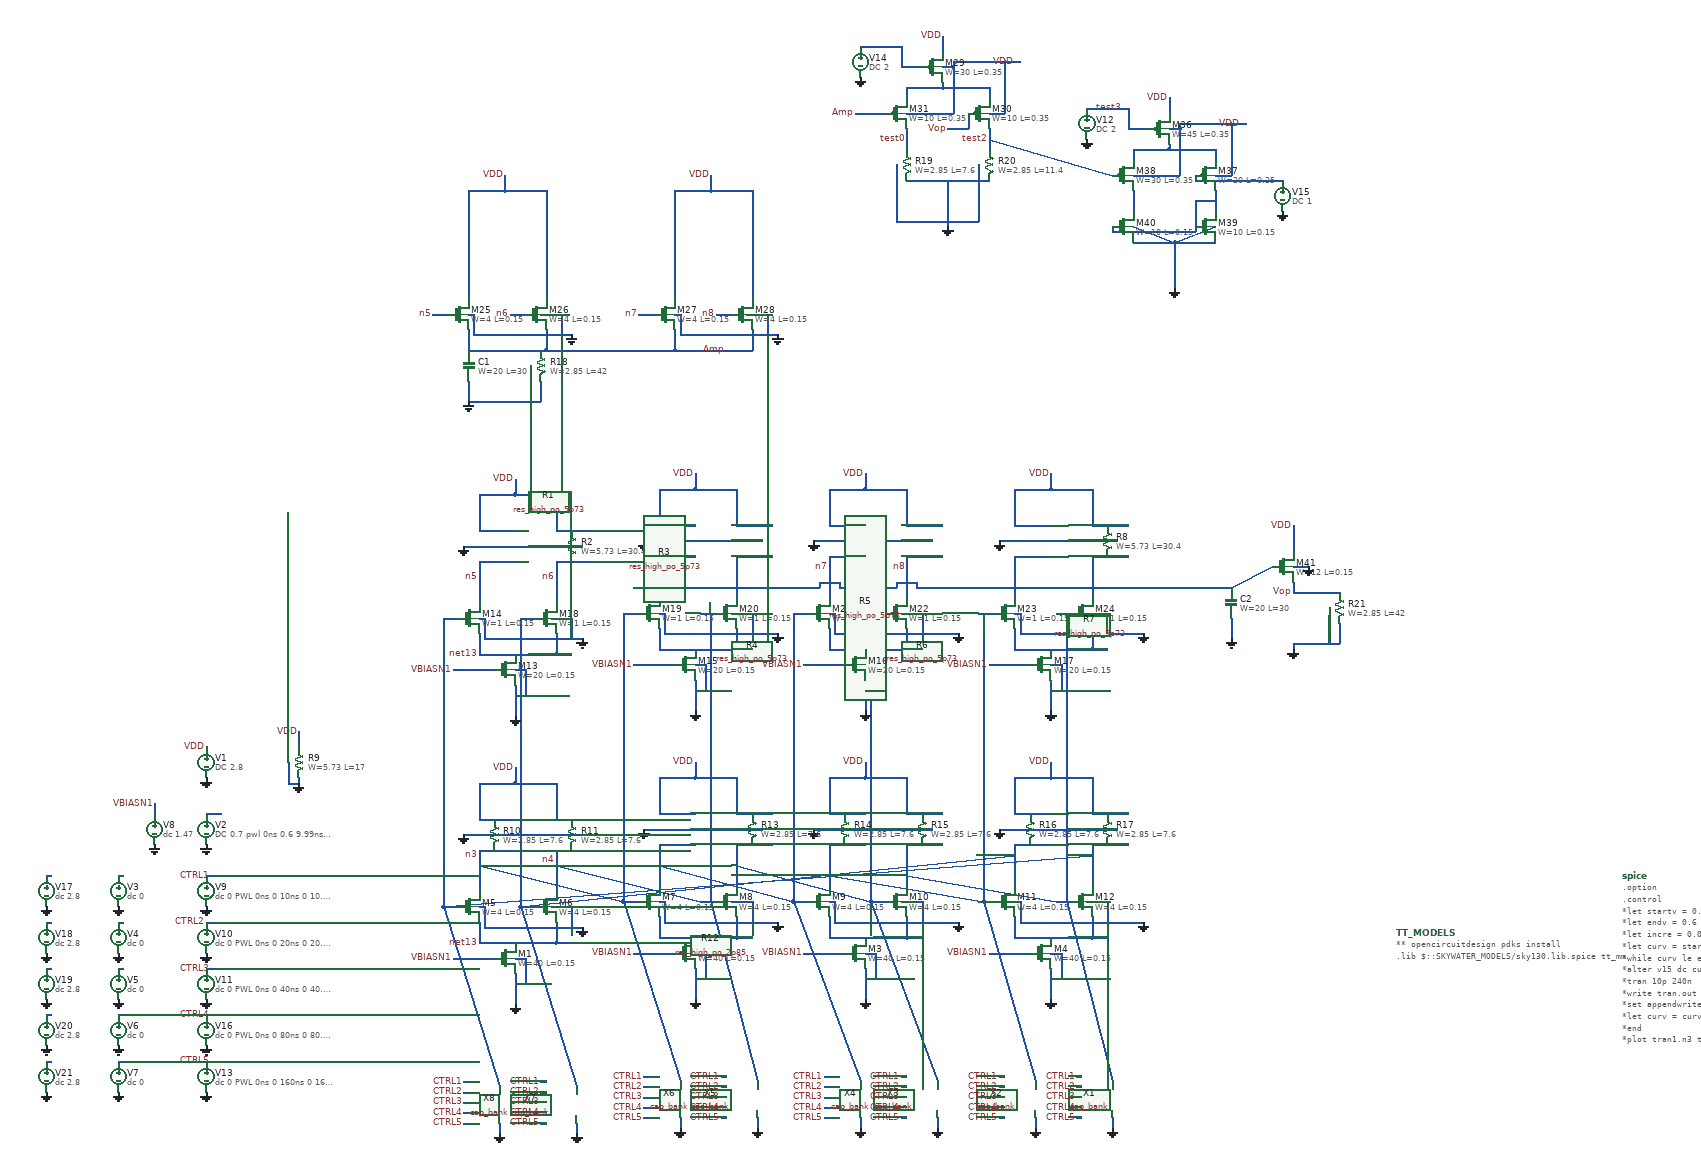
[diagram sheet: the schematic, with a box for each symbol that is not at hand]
v {xschem version=3.0.0 file_version=1.2 }
G {}
K {}
V {}
S {}
E {}
N 520 -180 520 -140 {
lab=GND}
N 450 -240 520 -240 {
lab=net13}
N 450 -280 450 -240 {
lab=net13}
N 520 -240 600 -240 {
lab=net13}
N 600 -280 600 -240 {
lab=net13}
N 600 -420 600 -340 {
lab=n4}
N 600 -550 600 -480 {
lab=VDD}
N 520 -550 600 -550 {
lab=VDD}
N 520 -580 520 -550 {
lab=VDD}
N 450 -550 520 -550 {
lab=VDD}
N 450 -550 450 -480 {
lab=VDD}
N 450 -420 450 -340 {
lab=n3}
N 380 -310 410 -310 {
lab=#net1}
N 530 -310 560 -310 {
lab=#net2}
N 400 -210 480 -210 {
lab=VBIASN1}
N 450 -310 460 -310 {
lab=GND}
N 520 -140 520 -120 {
lab=GND}
N 520 -210 540 -210 {
lab=GND}
N 540 -210 540 -160 {
lab=GND}
N 520 -160 540 -160 {
lab=GND}
N 590 -310 600 -310 {
lab=GND}
N 600 -310 630 -310 {
lab=GND}
N 600 -240 630 -240 {
lab=net13}
N 430 -450 580 -450 {
lab=GND}
N 420 -450 430 -450 {
lab=GND}
N 870 -190 870 -150 {
lab=GND}
N 800 -250 870 -250 {
lab=#net3}
N 800 -290 800 -250 {
lab=#net3}
N 870 -250 950 -250 {
lab=#net3}
N 950 -290 950 -250 {
lab=#net3}
N 950 -430 950 -350 {
lab=#net4}
N 950 -560 950 -490 {
lab=VDD}
N 870 -560 950 -560 {
lab=VDD}
N 870 -590 870 -560 {
lab=VDD}
N 800 -560 870 -560 {
lab=VDD}
N 800 -560 800 -490 {
lab=VDD}
N 800 -430 800 -350 {
lab=#net5}
N 730 -320 760 -320 {
lab=n3}
N 880 -320 910 -320 {
lab=n4}
N 750 -220 830 -220 {
lab=VBIASN1}
N 800 -320 810 -320 {
lab=GND}
N 870 -150 870 -130 {
lab=GND}
N 870 -220 890 -220 {
lab=GND}
N 890 -220 890 -170 {
lab=GND}
N 870 -170 890 -170 {
lab=GND}
N 940 -320 950 -320 {
lab=GND}
N 950 -320 980 -320 {
lab=GND}
N 950 -250 980 -250 {
lab=#net3}
N 780 -460 930 -460 {
lab=GND}
N 770 -460 780 -460 {
lab=GND}
N 1200 -190 1200 -150 {
lab=GND}
N 1130 -250 1200 -250 {
lab=#net6}
N 1130 -290 1130 -250 {
lab=#net6}
N 1200 -250 1280 -250 {
lab=#net6}
N 1280 -290 1280 -250 {
lab=#net6}
N 1280 -430 1280 -350 {
lab=#net7}
N 1280 -560 1280 -490 {
lab=VDD}
N 1200 -560 1280 -560 {
lab=VDD}
N 1200 -590 1200 -560 {
lab=VDD}
N 1130 -560 1200 -560 {
lab=VDD}
N 1130 -560 1130 -490 {
lab=VDD}
N 1130 -430 1130 -350 {
lab=#net8}
N 1060 -320 1090 -320 {
lab=#net5}
N 1210 -320 1240 -320 {
lab=#net4}
N 1080 -220 1160 -220 {
lab=VBIASN1}
N 1130 -320 1140 -320 {
lab=GND}
N 1200 -150 1200 -130 {
lab=GND}
N 1200 -220 1220 -220 {
lab=GND}
N 1220 -220 1220 -170 {
lab=GND}
N 1200 -170 1220 -170 {
lab=GND}
N 1270 -320 1280 -320 {
lab=GND}
N 1280 -320 1310 -320 {
lab=GND}
N 1280 -250 1310 -250 {
lab=#net6}
N 1110 -460 1260 -460 {
lab=GND}
N 1100 -460 1110 -460 {
lab=GND}
N 450 -390 730 -320 {
lab=n3}
N 600 -390 880 -320 {
lab=n4}
N 800 -390 1060 -320 {
lab=#net5}
N 950 -390 1210 -320 {
lab=#net4}
N 460 -310 460 -270 {
lab=GND}
N 460 -270 650 -270 {
lab=GND}
N 630 -310 630 -270 {
lab=GND}
N 810 -320 810 -280 {
lab=GND}
N 810 -280 1030 -280 {
lab=GND}
N 980 -320 980 -280 {
lab=GND}
N 1140 -320 1140 -280 {
lab=GND}
N 1140 -280 1380 -280 {
lab=GND}
N 1310 -320 1310 -280 {
lab=GND}
N 1560 -190 1560 -150 {
lab=GND}
N 1490 -250 1560 -250 {
lab=#net9}
N 1490 -290 1490 -250 {
lab=#net9}
N 1560 -250 1640 -250 {
lab=#net9}
N 1640 -290 1640 -250 {
lab=#net9}
N 1640 -430 1640 -350 {
lab=#net1}
N 1640 -560 1640 -490 {
lab=VDD}
N 1560 -560 1640 -560 {
lab=VDD}
N 1560 -590 1560 -560 {
lab=VDD}
N 1490 -560 1560 -560 {
lab=VDD}
N 1490 -560 1490 -490 {
lab=VDD}
N 1490 -430 1490 -350 {
lab=#net2}
N 1420 -320 1450 -320 {
lab=#net8}
N 1570 -320 1600 -320 {
lab=#net7}
N 1440 -220 1520 -220 {
lab=VBIASN1}
N 1490 -320 1500 -320 {
lab=GND}
N 1560 -150 1560 -130 {
lab=GND}
N 1560 -220 1580 -220 {
lab=GND}
N 1580 -220 1580 -170 {
lab=GND}
N 1560 -170 1580 -170 {
lab=GND}
N 1630 -320 1640 -320 {
lab=GND}
N 1640 -320 1670 -320 {
lab=GND}
N 1640 -250 1670 -250 {
lab=#net9}
N 1470 -460 1620 -460 {
lab=GND}
N 1460 -460 1470 -460 {
lab=GND}
N 1500 -320 1500 -280 {
lab=GND}
N 1500 -280 1740 -280 {
lab=GND}
N 1670 -320 1670 -280 {
lab=GND}
N 1130 -370 1430 -320 {
lab=#net8}
N 1280 -370 1570 -320 {
lab=#net7}
N 380 -310 1640 -410 {
lab=#net1}
N 530 -310 1490 -410 {
lab=#net2}
N -80 -490 -50 -490 {
lab=#net10}
N -80 -10 -70 -10 {
lab=CTRL5}
N -80 -100 -60 -100 {
lab=CTRL4}
N -80 -190 -60 -190 {
lab=CTRL3}
N -80 -280 -60 -280 {
lab=CTRL2}
N -80 -370 -60 -370 {
lab=CTRL1}
N -250 -370 -240 -370 {
lab=#net11}
N -250 -280 -240 -280 {
lab=#net12}
N -250 -190 -240 -190 {
lab=#net14}
N -250 -100 -240 -100 {
lab=#net15}
N -250 -10 -240 -10 {
lab=#net16}
N 450 -480 480 -480 {
lab=VDD}
N 480 -480 520 -480 {
lab=VDD}
N 480 -420 520 -420 {
lab=n3}
N 450 -420 480 -420 {
lab=n3}
N 600 -480 630 -480 {
lab=VDD}
N 630 -480 670 -480 {
lab=VDD}
N 630 -420 670 -420 {
lab=n4}
N 600 -420 630 -420 {
lab=n4}
N 800 -490 830 -490 {
lab=VDD}
N 830 -490 870 -490 {
lab=VDD}
N 830 -430 870 -430 {
lab=#net5}
N 800 -430 830 -430 {
lab=#net5}
N 950 -490 980 -490 {
lab=VDD}
N 980 -490 1020 -490 {
lab=VDD}
N 980 -430 1020 -430 {
lab=#net4}
N 950 -430 980 -430 {
lab=#net4}
N 1130 -490 1160 -490 {
lab=VDD}
N 1160 -490 1200 -490 {
lab=VDD}
N 1160 -430 1200 -430 {
lab=#net8}
N 1130 -430 1160 -430 {
lab=#net8}
N 1280 -490 1310 -490 {
lab=VDD}
N 1310 -490 1350 -490 {
lab=VDD}
N 1310 -430 1350 -430 {
lab=#net7}
N 1280 -430 1310 -430 {
lab=#net7}
N 1490 -490 1520 -490 {
lab=VDD}
N 1520 -490 1560 -490 {
lab=VDD}
N 1520 -430 1560 -430 {
lab=#net2}
N 1490 -430 1520 -430 {
lab=#net2}
N 1640 -490 1670 -490 {
lab=VDD}
N 1670 -490 1710 -490 {
lab=VDD}
N 1670 -430 1710 -430 {
lab=#net1}
N 1640 -430 1670 -430 {
lab=#net1}
N 580 -450 610 -450 {
lab=GND}
N 610 -450 650 -450 {
lab=GND}
N 930 -460 960 -460 {
lab=GND}
N 960 -460 1000 -460 {
lab=GND}
N 1260 -460 1290 -460 {
lab=GND}
N 1290 -460 1330 -460 {
lab=GND}
N 1620 -460 1650 -460 {
lab=GND}
N 1650 -460 1690 -460 {
lab=GND}
N -180 -510 -180 -490 {
lab=VBIASN1}
N 520 -740 520 -700 {
lab=GND}
N 450 -800 520 -800 {
lab=net13}
N 450 -840 450 -800 {
lab=net13}
N 520 -800 600 -800 {
lab=net13}
N 600 -840 600 -800 {
lab=net13}
N 600 -980 600 -900 {
lab=n6}
N 600 -1110 600 -1040 {
lab=VDD}
N 520 -1110 600 -1110 {
lab=VDD}
N 520 -1140 520 -1110 {
lab=VDD}
N 450 -1110 520 -1110 {
lab=VDD}
N 450 -1110 450 -1040 {
lab=VDD}
N 450 -980 450 -900 {
lab=n5}
N 380 -870 410 -870 {
lab=#net1}
N 530 -870 560 -870 {
lab=#net2}
N 400 -770 480 -770 {
lab=VBIASN1}
N 450 -870 460 -870 {
lab=GND}
N 520 -700 520 -680 {
lab=GND}
N 520 -770 540 -770 {
lab=GND}
N 540 -770 540 -720 {
lab=GND}
N 520 -720 540 -720 {
lab=GND}
N 590 -870 600 -870 {
lab=GND}
N 600 -870 630 -870 {
lab=GND}
N 600 -800 630 -800 {
lab=net13}
N 430 -1010 580 -1010 {
lab=GND}
N 420 -1010 430 -1010 {
lab=GND}
N 870 -750 870 -710 {
lab=GND}
N 800 -810 870 -810 {
lab=#net17}
N 800 -850 800 -810 {
lab=#net17}
N 870 -810 950 -810 {
lab=#net17}
N 950 -850 950 -810 {
lab=#net17}
N 950 -990 950 -910 {
lab=#net18}
N 950 -1120 950 -1050 {
lab=VDD}
N 870 -1120 950 -1120 {
lab=VDD}
N 870 -1150 870 -1120 {
lab=VDD}
N 800 -1120 870 -1120 {
lab=VDD}
N 800 -1120 800 -1050 {
lab=VDD}
N 800 -990 800 -910 {
lab=#net18}
N 730 -880 760 -880 {
lab=n3}
N 880 -880 910 -880 {
lab=n4}
N 750 -780 830 -780 {
lab=VBIASN1}
N 800 -880 810 -880 {
lab=GND}
N 870 -710 870 -690 {
lab=GND}
N 870 -780 890 -780 {
lab=GND}
N 890 -780 890 -730 {
lab=GND}
N 870 -730 890 -730 {
lab=GND}
N 940 -880 950 -880 {
lab=GND}
N 950 -880 980 -880 {
lab=GND}
N 950 -810 980 -810 {
lab=#net17}
N 780 -1020 930 -1020 {
lab=GND}
N 770 -1020 780 -1020 {
lab=GND}
N 1200 -750 1200 -710 {
lab=GND}
N 1130 -810 1200 -810 {
lab=#net19}
N 1130 -850 1130 -810 {
lab=#net19}
N 1200 -810 1280 -810 {
lab=#net19}
N 1280 -850 1280 -810 {
lab=#net19}
N 1280 -990 1280 -910 {
lab=n8}
N 1280 -1120 1280 -1050 {
lab=VDD}
N 1200 -1120 1280 -1120 {
lab=VDD}
N 1200 -1150 1200 -1120 {
lab=VDD}
N 1130 -1120 1200 -1120 {
lab=VDD}
N 1130 -1120 1130 -1050 {
lab=VDD}
N 1130 -990 1130 -910 {
lab=n7}
N 1060 -880 1090 -880 {
lab=#net5}
N 1210 -880 1240 -880 {
lab=#net4}
N 1080 -780 1160 -780 {
lab=VBIASN1}
N 1130 -880 1140 -880 {
lab=GND}
N 1200 -710 1200 -690 {
lab=GND}
N 1200 -780 1220 -780 {
lab=GND}
N 1220 -780 1220 -730 {
lab=GND}
N 1200 -730 1220 -730 {
lab=GND}
N 1270 -880 1280 -880 {
lab=GND}
N 1280 -880 1310 -880 {
lab=GND}
N 1280 -810 1310 -810 {
lab=#net19}
N 1110 -1020 1260 -1020 {
lab=GND}
N 1100 -1020 1110 -1020 {
lab=GND}
N 460 -870 460 -830 {
lab=GND}
N 460 -830 650 -830 {
lab=GND}
N 630 -870 630 -830 {
lab=GND}
N 810 -880 810 -840 {
lab=GND}
N 810 -840 1030 -840 {
lab=GND}
N 980 -880 980 -840 {
lab=GND}
N 1140 -880 1140 -840 {
lab=GND}
N 1140 -840 1380 -840 {
lab=GND}
N 1310 -880 1310 -840 {
lab=GND}
N 1560 -750 1560 -710 {
lab=GND}
N 1490 -810 1560 -810 {
lab=#net20}
N 1490 -850 1490 -810 {
lab=#net20}
N 1560 -810 1640 -810 {
lab=#net20}
N 1640 -850 1640 -810 {
lab=#net20}
N 1640 -990 1640 -910 {
lab=#net18}
N 1640 -1120 1640 -1050 {
lab=VDD}
N 1560 -1120 1640 -1120 {
lab=VDD}
N 1560 -1150 1560 -1120 {
lab=VDD}
N 1490 -1120 1560 -1120 {
lab=VDD}
N 1490 -1120 1490 -1050 {
lab=VDD}
N 1490 -990 1490 -910 {
lab=#net18}
N 1420 -880 1450 -880 {
lab=#net8}
N 1570 -880 1600 -880 {
lab=#net7}
N 1440 -780 1520 -780 {
lab=VBIASN1}
N 1490 -880 1500 -880 {
lab=GND}
N 1560 -710 1560 -690 {
lab=GND}
N 1560 -780 1580 -780 {
lab=GND}
N 1580 -780 1580 -730 {
lab=GND}
N 1560 -730 1580 -730 {
lab=GND}
N 1630 -880 1640 -880 {
lab=GND}
N 1640 -880 1670 -880 {
lab=GND}
N 1640 -810 1670 -810 {
lab=#net20}
N 1470 -1020 1620 -1020 {
lab=GND}
N 1460 -1020 1470 -1020 {
lab=GND}
N 1500 -880 1500 -840 {
lab=GND}
N 1500 -840 1740 -840 {
lab=GND}
N 1670 -880 1670 -840 {
lab=GND}
N 450 -1040 480 -1040 {
lab=VDD}
N 480 -1040 520 -1040 {
lab=VDD}
N 480 -980 520 -980 {
lab=n5}
N 450 -980 480 -980 {
lab=n5}
N 600 -1040 630 -1040 {
lab=VDD}
N 630 -1040 670 -1040 {
lab=VDD}
N 630 -980 670 -980 {
lab=n6}
N 600 -980 630 -980 {
lab=n6}
N 800 -1050 830 -1050 {
lab=VDD}
N 830 -1050 870 -1050 {
lab=VDD}
N 830 -990 870 -990 {
lab=#net18}
N 800 -990 830 -990 {
lab=#net18}
N 950 -1050 980 -1050 {
lab=VDD}
N 980 -1050 1020 -1050 {
lab=VDD}
N 980 -990 1020 -990 {
lab=#net18}
N 950 -990 980 -990 {
lab=#net18}
N 1130 -1050 1160 -1050 {
lab=VDD}
N 1160 -1050 1200 -1050 {
lab=VDD}
N 1160 -990 1200 -990 {
lab=n7}
N 1130 -990 1160 -990 {
lab=n7}
N 1280 -1050 1310 -1050 {
lab=VDD}
N 1310 -1050 1350 -1050 {
lab=VDD}
N 1310 -990 1350 -990 {
lab=n8}
N 1280 -990 1310 -990 {
lab=n8}
N 1490 -1050 1520 -1050 {
lab=VDD}
N 1520 -1050 1560 -1050 {
lab=VDD}
N 1520 -990 1560 -990 {
lab=#net18}
N 1490 -990 1520 -990 {
lab=#net18}
N 1640 -1050 1670 -1050 {
lab=VDD}
N 1670 -1050 1710 -1050 {
lab=VDD}
N 1670 -990 1710 -990 {
lab=#net18}
N 1640 -990 1670 -990 {
lab=#net18}
N 580 -1010 610 -1010 {
lab=GND}
N 610 -1010 650 -1010 {
lab=GND}
N 930 -1020 960 -1020 {
lab=GND}
N 960 -1020 1000 -1020 {
lab=GND}
N 1260 -1020 1290 -1020 {
lab=GND}
N 1290 -1020 1330 -1020 {
lab=GND}
N 1620 -1020 1650 -1020 {
lab=GND}
N 1650 -1020 1690 -1020 {
lab=GND}
N 380 -870 380 -310 {
lab=#net1}
N 530 -870 530 -310 {
lab=#net2}
N 730 -880 730 -320 {
lab=n3}
N 1060 -880 1060 -320 {
lab=#net5}
N 1210 -880 1210 -310 {
lab=#net4}
N 1430 -880 1430 -320 {
lab=#net8}
N 900 -880 900 -320 {
lab=n4}
N 1590 -880 1590 -320 {
lab=#net7}
N 1680 100 1680 120 {
lab=GND}
N 1610 100 1620 100 {
lab=CTRL5}
N 1610 80 1620 80 {
lab=CTRL4}
N 1610 60 1620 60 {
lab=CTRL3}
N 1610 40 1620 40 {
lab=CTRL2}
N 1610 20 1620 20 {
lab=CTRL1}
N 1530 100 1530 120 {
lab=GND}
N 1460 100 1470 100 {
lab=CTRL5}
N 1460 80 1470 80 {
lab=CTRL4}
N 1460 60 1470 60 {
lab=CTRL3}
N 1460 40 1470 40 {
lab=CTRL2}
N 1460 20 1470 20 {
lab=CTRL1}
N 1340 100 1340 120 {
lab=GND}
N 1270 100 1280 100 {
lab=CTRL5}
N 1270 80 1280 80 {
lab=CTRL4}
N 1270 60 1280 60 {
lab=CTRL3}
N 1270 40 1280 40 {
lab=CTRL2}
N 1270 20 1280 20 {
lab=CTRL1}
N 1190 100 1190 120 {
lab=GND}
N 1120 100 1130 100 {
lab=CTRL5}
N 1120 80 1130 80 {
lab=CTRL4}
N 1120 60 1130 60 {
lab=CTRL3}
N 1120 40 1130 40 {
lab=CTRL2}
N 1120 20 1130 20 {
lab=CTRL1}
N 990 100 990 120 {
lab=GND}
N 920 100 930 100 {
lab=CTRL5}
N 920 80 930 80 {
lab=CTRL4}
N 920 60 930 60 {
lab=CTRL3}
N 920 40 930 40 {
lab=CTRL2}
N 920 20 930 20 {
lab=CTRL1}
N 840 100 840 120 {
lab=GND}
N 770 100 780 100 {
lab=CTRL5}
N 770 80 780 80 {
lab=CTRL4}
N 770 60 780 60 {
lab=CTRL3}
N 770 40 780 40 {
lab=CTRL2}
N 770 20 780 20 {
lab=CTRL1}
N 640 110 640 130 {
lab=GND}
N 570 110 580 110 {
lab=CTRL5}
N 570 90 580 90 {
lab=CTRL4}
N 570 70 580 70 {
lab=CTRL3}
N 570 50 580 50 {
lab=CTRL2}
N 570 30 580 30 {
lab=CTRL1}
N 490 110 490 130 {
lab=GND}
N 420 110 430 110 {
lab=CTRL5}
N 420 90 430 90 {
lab=CTRL4}
N 420 70 430 70 {
lab=CTRL3}
N 420 50 430 50 {
lab=CTRL2}
N 420 30 430 30 {
lab=CTRL1}
N 380 -310 490 40 {
lab=#net1}
N 530 -310 640 40 {
lab=#net2}
N 730 -320 840 30 {
lab=n3}
N 900 -320 990 30 {
lab=n4}
N 1060 -320 1190 30 {
lab=#net5}
N 1210 -320 1340 30 {
lab=#net4}
N 1430 -320 1530 30 {
lab=#net8}
N 1590 -320 1680 30 {
lab=#net7}
N 100 -560 100 -550 {
lab=GND}
N 100 -650 100 -620 {
lab=VDD}
N 80 -590 80 -550 {
lab=GND}
N 80 -550 100 -550 {
lab=GND}
N 800 -930 950 -930 {
lab=#net18}
N 1490 -930 1640 -930 {
lab=#net18}
N 2120 -860 2120 -820 {
lab=GND}
N 2030 -820 2120 -820 {
lab=GND}
N 2030 -1050 2030 -1010 {
lab=VDD}
N 2030 -1010 2030 -1000 {
lab=VDD}
N 2030 -920 2120 -920 {
lab=Vop}
N 2030 -970 2060 -970 {
lab=GND}
N 1910 -870 1910 -830 {
lab=GND}
N 1910 -930 1990 -970 {
lab=#net18}
N 430 -1430 430 -1390 {
lab=Amp}
N 500 -1390 580 -1390 {
lab=Amp}
N 580 -1430 580 -1390 {
lab=Amp}
N 580 -1570 580 -1490 {
lab=VDD}
N 580 -1700 580 -1630 {
lab=VDD}
N 500 -1700 580 -1700 {
lab=VDD}
N 500 -1730 500 -1700 {
lab=VDD}
N 430 -1700 500 -1700 {
lab=VDD}
N 430 -1700 430 -1630 {
lab=VDD}
N 430 -1570 430 -1490 {
lab=VDD}
N 360 -1460 390 -1460 {
lab=n5}
N 510 -1460 540 -1460 {
lab=n6}
N 430 -1460 440 -1460 {
lab=GND}
N 570 -1460 580 -1460 {
lab=GND}
N 580 -1460 610 -1460 {
lab=GND}
N 440 -1460 440 -1420 {
lab=GND}
N 440 -1420 630 -1420 {
lab=GND}
N 610 -1460 610 -1420 {
lab=GND}
N 430 -1330 430 -1290 {
lab=GND}
N 430 -1390 500 -1390 {
lab=Amp}
N 430 -1630 430 -1570 {
lab=VDD}
N 580 -1630 580 -1570 {
lab=VDD}
N 570 -1330 570 -1290 {
lab=GND}
N 500 -1290 570 -1290 {
lab=GND}
N 430 -1290 500 -1290 {
lab=GND}
N 950 -930 1110 -930 {
lab=#net18}
N 1110 -940 1110 -930 {
lab=#net18}
N 1110 -940 1150 -940 {
lab=#net18}
N 1150 -940 1150 -930 {
lab=#net18}
N 1150 -930 1260 -930 {
lab=#net18}
N 1260 -940 1260 -930 {
lab=#net18}
N 1260 -940 1300 -940 {
lab=#net18}
N 1300 -940 1300 -930 {
lab=#net18}
N 1300 -930 1490 -930 {
lab=#net18}
N 750 -930 800 -930 {
lab=#net18}
N 1890 -930 1910 -930 {
lab=#net18}
N 830 -1430 830 -1390 {
lab=Amp}
N 900 -1390 980 -1390 {
lab=Amp}
N 980 -1430 980 -1390 {
lab=Amp}
N 980 -1570 980 -1490 {
lab=VDD}
N 980 -1700 980 -1630 {
lab=VDD}
N 900 -1700 980 -1700 {
lab=VDD}
N 900 -1730 900 -1700 {
lab=VDD}
N 830 -1700 900 -1700 {
lab=VDD}
N 830 -1700 830 -1630 {
lab=VDD}
N 830 -1570 830 -1490 {
lab=VDD}
N 760 -1460 790 -1460 {
lab=n7}
N 910 -1460 940 -1460 {
lab=n8}
N 830 -1460 840 -1460 {
lab=GND}
N 970 -1460 980 -1460 {
lab=GND}
N 980 -1460 1010 -1460 {
lab=GND}
N 840 -1460 840 -1420 {
lab=GND}
N 840 -1420 1030 -1420 {
lab=GND}
N 1010 -1460 1010 -1420 {
lab=GND}
N 830 -1390 900 -1390 {
lab=Amp}
N 830 -1630 830 -1570 {
lab=VDD}
N 980 -1630 980 -1570 {
lab=VDD}
N 1840 -930 1890 -930 {
lab=#net18}
N 580 -1390 830 -1390 {
lab=Amp}
N 1350 -2000 1350 -1970 {
lab=VDD}
N 1190 -1980 1270 -1980 {
lab=#net21}
N 1270 -1980 1270 -1940 {
lab=#net21}
N 1270 -1940 1310 -1940 {
lab=#net21}
N 1350 -1910 1350 -1900 {
lab=#net22}
N 1280 -1900 1350 -1900 {
lab=#net22}
N 1280 -1900 1280 -1880 {
lab=#net22}
N 1350 -1900 1440 -1900 {
lab=#net22}
N 1440 -1900 1440 -1880 {
lab=#net22}
N 1280 -1820 1280 -1780 {
lab=test0}
N 1440 -1820 1440 -1780 {
lab=test2}
N 1280 -1720 1440 -1720 {
lab=GND}
N 1360 -1720 1360 -1700 {
lab=GND}
N 1470 -1950 1500 -1950 {
lab=VDD}
N 1470 -1950 1470 -1850 {
lab=VDD}
N 1440 -1850 1470 -1850 {
lab=VDD}
N 1370 -1950 1470 -1950 {
lab=VDD}
N 1370 -1950 1370 -1940 {
lab=VDD}
N 1350 -1940 1370 -1940 {
lab=VDD}
N 1370 -1940 1370 -1850 {
lab=VDD}
N 1280 -1850 1370 -1850 {
lab=VDD}
N 1360 -1700 1360 -1630 {
lab=GND}
N 1790 -1880 1790 -1850 {
lab=VDD}
N 1630 -1860 1710 -1860 {
lab=test3}
N 1710 -1860 1710 -1820 {
lab=test3}
N 1710 -1820 1750 -1820 {
lab=test3}
N 1790 -1790 1790 -1780 {
lab=#net23}
N 1720 -1780 1790 -1780 {
lab=#net23}
N 1720 -1780 1720 -1760 {
lab=#net23}
N 1790 -1780 1880 -1780 {
lab=#net23}
N 1880 -1780 1880 -1760 {
lab=#net23}
N 1840 -1730 1840 -1720 {
lab=#net24}
N 1840 -1720 2010 -1720 {
lab=#net24}
N 1720 -1700 1720 -1660 {
lab=#net25}
N 1880 -1700 1880 -1660 {
lab=#net26}
N 1720 -1600 1880 -1600 {
lab=GND}
N 1800 -1600 1800 -1580 {
lab=GND}
N 1910 -1830 1940 -1830 {
lab=VDD}
N 1910 -1830 1910 -1730 {
lab=VDD}
N 1880 -1730 1910 -1730 {
lab=VDD}
N 1810 -1830 1910 -1830 {
lab=VDD}
N 1810 -1830 1810 -1820 {
lab=VDD}
N 1790 -1820 1810 -1820 {
lab=VDD}
N 1810 -1820 1810 -1730 {
lab=VDD}
N 1720 -1730 1810 -1730 {
lab=VDD}
N 1800 -1580 1800 -1510 {
lab=GND}
N 1840 -1680 1840 -1630 {
lab=#net26}
N 1840 -1680 1880 -1680 {
lab=#net26}
N 1840 -1630 1840 -1620 {
lab=#net26}
N 1680 -1620 1840 -1620 {
lab=#net26}
N 1680 -1630 1680 -1620 {
lab=#net26}
N 1720 -1630 1800 -1600 {
lab=GND}
N 1800 -1600 1880 -1630 {
lab=GND}
N 1440 -1800 1680 -1730 {
lab=test2}
N 1180 -1850 1240 -1850 {
lab=Amp}
N 1400 -1850 1400 -1820 {
lab=Vop}
N 1360 -1820 1400 -1820 {
lab=Vop}
N 2030 -940 2030 -920 {
lab=Vop}
N 2030 -820 2030 -810 {
lab=GND}
N 550 -1360 550 -1290 {
lab=GND}
N 2100 -890 2100 -820 {
lab=GND}
N 1260 -1750 1260 -1640 {
lab=GND}
N 1260 -1640 1360 -1640 {
lab=GND}
N 1420 -1750 1420 -1640 {
lab=GND}
N 1360 -1640 1420 -1640 {
lab=GND}
N -390 -370 -380 -370 {
lab=#net27}
N -390 -280 -380 -280 {
lab=#net28}
N -390 -190 -380 -190 {
lab=#net29}
N -390 -100 -380 -100 {
lab=#net30}
N -390 -10 -380 -10 {
lab=#net31}
N 1640 -930 1840 -930 {
lab=#net18}
C {code.sym} 2230 -260 0 0 {name=TT_MODELS
only_toplevel=true
format="tcleval( @value )"
value="
** opencircuitdesign pdks install
.lib $::SKYWATER_MODELS/sky130.lib.spice tt_mm

"
spice_ignore=false}
C {vsource.sym} -80 -590 0 0 {name=V1 value="DC 2.8"}
C {gnd.sym} -80 -560 0 0 {name=l12 lab=GND}
C {vsource.sym} -80 -460 0 0 {name=V2 value="DC 0.7 pwl 0ns 0.6 9.99ns 1 10ns 0.7 r=0" }
C {gnd.sym} -80 -430 0 0 {name=l15 lab=GND}
C {lab_pin.sym} -80 -620 0 0 {name=l18 sig_type=std_logic lab=VDD
}
C {gnd.sym} 520 -120 0 0 {name=l2 lab=GND}
C {lab_pin.sym} 520 -580 0 0 {name=l8 sig_type=std_logic lab=VDD
}
C {gnd.sym} 420 -450 0 0 {name=l25 lab=GND}
C {gnd.sym} 870 -130 0 0 {name=l26 lab=GND}
C {lab_pin.sym} 870 -590 0 0 {name=l39 sig_type=std_logic lab=VDD
}
C {gnd.sym} 770 -460 0 0 {name=l44 lab=GND}
C {gnd.sym} 1200 -130 0 0 {name=l45 lab=GND}
C {lab_pin.sym} 1200 -590 0 0 {name=l46 sig_type=std_logic lab=VDD
}
C {gnd.sym} 1100 -460 0 0 {name=l47 lab=GND}
C {lab_pin.sym} 400 -210 0 0 {name=l48 sig_type=std_logic lab=VBIASN1}
C {lab_pin.sym} 750 -220 0 0 {name=l49 sig_type=std_logic lab=VBIASN1}
C {lab_pin.sym} 1080 -220 0 0 {name=l50 sig_type=std_logic lab=VBIASN1}
C {sky130_fd_pr/nfet_01v8_lvt.sym} 500 -210 0 0 {name=M1
L=0.15
W=40
nf=40
mult=1
ad="'int((nf+1)/2) * W/nf * 0.29'" 
pd="'2*int((nf+1)/2) * (W/nf + 0.29)'"
as="'int((nf+2)/2) * W/nf * 0.29'" 
ps="'2*int((nf+2)/2) * (W/nf + 0.29)'"
nrd="'0.29 / W'" nrs="'0.29 / W'"
sa=0 sb=0 sd=0
model=nfet_01v8_lvt
spiceprefix=X
}
C {lab_pin.sym} 450 -240 0 0 {name=l51 sig_type=std_logic lab=net13}
C {gnd.sym} 1560 -130 0 0 {name=l52 lab=GND}
C {lab_pin.sym} 1560 -590 0 0 {name=l53 sig_type=std_logic lab=VDD
}
C {gnd.sym} 1460 -460 0 0 {name=l54 lab=GND}
C {lab_pin.sym} 1440 -220 0 0 {name=l55 sig_type=std_logic lab=VBIASN1}
C {lab_pin.sym} 450 -410 0 0 {name=l58 sig_type=std_logic lab=n3}
C {lab_pin.sym} 600 -400 0 0 {name=l60 sig_type=std_logic lab=n4}
C {sky130_fd_pr/nfet_01v8_lvt.sym} 430 -310 0 0 {name=M5
L=0.15
W=4
nf=4
mult=1
ad="'int((nf+1)/2) * W/nf * 0.29'" 
pd="'2*int((nf+1)/2) * (W/nf + 0.29)'"
as="'int((nf+2)/2) * W/nf * 0.29'" 
ps="'2*int((nf+2)/2) * (W/nf + 0.29)'"
nrd="'0.29 / W'" nrs="'0.29 / W'"
sa=0 sb=0 sd=0
model=nfet_01v8_lvt
spiceprefix=X
}
C {vsource.sym} -80 -340 0 0 {name=V9 value="dc 0 PWL 0ns 0 10ns 0 10.001ns 2.8 20ns 2.8 r=0" 
}
C {gnd.sym} -80 -310 0 0 {name=l112 lab=GND}
C {gnd.sym} -80 -220 0 0 {name=l114 lab=GND}
C {gnd.sym} -80 -130 0 0 {name=l116 lab=GND}
C {gnd.sym} -80 -40 0 0 {name=l118 lab=GND}
C {gnd.sym} -80 50 0 0 {name=l120 lab=GND}
C {vsource.sym} -250 -340 0 0 {name=V3 value="dc 0"}
C {gnd.sym} -250 -310 0 0 {name=l24 lab=GND}
C {lab_pin.sym} -70 -370 0 0 {name=l27 sig_type=std_logic lab=CTRL1
}
C {gnd.sym} -250 -220 0 0 {name=l29 lab=GND}
C {lab_pin.sym} -80 -280 0 0 {name=l30 sig_type=std_logic lab=CTRL2
}
C {gnd.sym} -250 -130 0 0 {name=l31 lab=GND}
C {lab_pin.sym} -70 -190 0 0 {name=l32 sig_type=std_logic lab=CTRL3
}
C {gnd.sym} -250 -40 0 0 {name=l33 lab=GND}
C {lab_pin.sym} -70 -100 0 0 {name=l34 sig_type=std_logic lab=CTRL4
}
C {gnd.sym} -250 50 0 0 {name=l35 lab=GND}
C {lab_pin.sym} -70 -10 0 0 {name=l36 sig_type=std_logic lab=CTRL5
}
C {vsource.sym} -250 -250 0 0 {name=V4 value="dc 0" 
}
C {vsource.sym} -250 -160 0 0 {name=V5 value="dc 0" 
}
C {vsource.sym} -250 -70 0 0 {name=V6 value="dc 0" 
}
C {vsource.sym} -250 20 0 0 {name=V7 value="dc 0"
}
C {gnd.sym} 650 -270 0 0 {name=l17 lab=GND}
C {gnd.sym} 1030 -280 0 0 {name=l37 lab=GND}
C {gnd.sym} 1380 -280 0 0 {name=l38 lab=GND}
C {gnd.sym} 1740 -280 0 0 {name=l40 lab=GND}
C {vsource.sym} -80 -250 0 0 {name=V10 value="dc 0 PWL 0ns 0 20ns 0 20.001ns 2.8 40ns 2.8 r=0" 
}
C {vsource.sym} -80 -160 0 0 {name=V11 value="dc 0 PWL 0ns 0 40ns 0 40.001ns 2.8 80ns 2.8 r=0" 
}
C {vsource.sym} -80 20 0 0 {name=V13 value="dc 0 PWL 0ns 0 160ns 0 160.001n 2.8" 
}
C {vsource.sym} -80 -70 0 0 {name=V16 value="dc 0 PWL 0ns 0 80ns 0 80.001ns 2.8 160ns 2.8 r=0" 
}
C {code_shown.sym} 2670 -370 0 0 {name=spice only_toplevel=false value="
.option
.control
*let startv = 0.2
*let endv = 0.6
*let incre = 0.05
*let curv = startv
*while curv le endv
*alter v15 dc curv
*tran 10p 240n
*write tran.out n3 n3-n4
*set appendwrite
*let curv = curv + incre
*end
*plot tran1.n3 tran2.n3 tran3.n3 tran4.n3 tran5.n3 tran6.n3 tran7.n3 tran8.n3 tran9.n3 tran10.n3
*plot vbiasn1 tran1.test3 tran2.test3 tran3.test3 tran4.test3 tran5.test3 tran6.test3 tran7.test3 tran8.test3 tran9.test3 tran10.test3
*tran 1p 40n 30n
*plot n3 n5
*fft n3-n4 n5-n6


.endc
"}
C {lab_pin.sym} -180 -510 0 0 {name=l1 sig_type=std_logic lab=VBIASN1}
C {vsource.sym} -180 -460 0 0 {name=V8 value="dc 1.47"}
C {gnd.sym} -180 -430 0 0 {name=l3 lab=GND}
C {sky130_fd_pr/nfet_01v8_lvt.sym} 580 -310 0 0 {name=M6
L=0.15
W=4
nf=4
mult=1
ad="'int((nf+1)/2) * W/nf * 0.29'" 
pd="'2*int((nf+1)/2) * (W/nf + 0.29)'"
as="'int((nf+2)/2) * W/nf * 0.29'" 
ps="'2*int((nf+2)/2) * (W/nf + 0.29)'"
nrd="'0.29 / W'" nrs="'0.29 / W'"
sa=0 sb=0 sd=0
model=nfet_01v8_lvt
spiceprefix=X
}
C {sky130_fd_pr/nfet_01v8_lvt.sym} 780 -320 0 0 {name=M7
L=0.15
W=4
nf=4
mult=1
ad="'int((nf+1)/2) * W/nf * 0.29'" 
pd="'2*int((nf+1)/2) * (W/nf + 0.29)'"
as="'int((nf+2)/2) * W/nf * 0.29'" 
ps="'2*int((nf+2)/2) * (W/nf + 0.29)'"
nrd="'0.29 / W'" nrs="'0.29 / W'"
sa=0 sb=0 sd=0
model=nfet_01v8_lvt
spiceprefix=X
}
C {sky130_fd_pr/nfet_01v8_lvt.sym} 930 -320 0 0 {name=M8
L=0.15
W=4
nf=4
mult=1
ad="'int((nf+1)/2) * W/nf * 0.29'" 
pd="'2*int((nf+1)/2) * (W/nf + 0.29)'"
as="'int((nf+2)/2) * W/nf * 0.29'" 
ps="'2*int((nf+2)/2) * (W/nf + 0.29)'"
nrd="'0.29 / W'" nrs="'0.29 / W'"
sa=0 sb=0 sd=0
model=nfet_01v8_lvt
spiceprefix=X
}
C {sky130_fd_pr/nfet_01v8_lvt.sym} 1110 -320 0 0 {name=M9
L=0.15
W=4
nf=4
mult=1
ad="'int((nf+1)/2) * W/nf * 0.29'" 
pd="'2*int((nf+1)/2) * (W/nf + 0.29)'"
as="'int((nf+2)/2) * W/nf * 0.29'" 
ps="'2*int((nf+2)/2) * (W/nf + 0.29)'"
nrd="'0.29 / W'" nrs="'0.29 / W'"
sa=0 sb=0 sd=0
model=nfet_01v8_lvt
spiceprefix=X
}
C {sky130_fd_pr/nfet_01v8_lvt.sym} 1260 -320 0 0 {name=M10
L=0.15
W=4
nf=4
mult=1
ad="'int((nf+1)/2) * W/nf * 0.29'" 
pd="'2*int((nf+1)/2) * (W/nf + 0.29)'"
as="'int((nf+2)/2) * W/nf * 0.29'" 
ps="'2*int((nf+2)/2) * (W/nf + 0.29)'"
nrd="'0.29 / W'" nrs="'0.29 / W'"
sa=0 sb=0 sd=0
model=nfet_01v8_lvt
spiceprefix=X
}
C {sky130_fd_pr/nfet_01v8_lvt.sym} 1470 -320 0 0 {name=M11
L=0.15
W=4
nf=4
mult=1
ad="'int((nf+1)/2) * W/nf * 0.29'" 
pd="'2*int((nf+1)/2) * (W/nf + 0.29)'"
as="'int((nf+2)/2) * W/nf * 0.29'" 
ps="'2*int((nf+2)/2) * (W/nf + 0.29)'"
nrd="'0.29 / W'" nrs="'0.29 / W'"
sa=0 sb=0 sd=0
model=nfet_01v8_lvt
spiceprefix=X
}
C {sky130_fd_pr/nfet_01v8_lvt.sym} 1620 -320 0 0 {name=M12
L=0.15
W=4
nf=4
mult=1
ad="'int((nf+1)/2) * W/nf * 0.29'" 
pd="'2*int((nf+1)/2) * (W/nf + 0.29)'"
as="'int((nf+2)/2) * W/nf * 0.29'" 
ps="'2*int((nf+2)/2) * (W/nf + 0.29)'"
nrd="'0.29 / W'" nrs="'0.29 / W'"
sa=0 sb=0 sd=0
model=nfet_01v8_lvt
spiceprefix=X
}
C {gnd.sym} 520 -680 0 0 {name=l4 lab=GND}
C {lab_pin.sym} 520 -1140 0 0 {name=l5 sig_type=std_logic lab=VDD
}
C {gnd.sym} 420 -1010 0 0 {name=l6 lab=GND}
C {gnd.sym} 870 -690 0 0 {name=l7 lab=GND}
C {lab_pin.sym} 870 -1150 0 0 {name=l9 sig_type=std_logic lab=VDD
}
C {gnd.sym} 770 -1020 0 0 {name=l10 lab=GND}
C {gnd.sym} 1200 -690 0 0 {name=l11 lab=GND}
C {lab_pin.sym} 1200 -1150 0 0 {name=l13 sig_type=std_logic lab=VDD
}
C {gnd.sym} 1100 -1020 0 0 {name=l14 lab=GND}
C {lab_pin.sym} 400 -770 0 0 {name=l16 sig_type=std_logic lab=VBIASN1}
C {lab_pin.sym} 750 -780 0 0 {name=l19 sig_type=std_logic lab=VBIASN1}
C {lab_pin.sym} 1080 -780 0 0 {name=l20 sig_type=std_logic lab=VBIASN1}
C {sky130_fd_pr/nfet_01v8_lvt.sym} 500 -770 0 0 {name=M13
L=0.15
W=20
nf=20
mult=1
ad="'int((nf+1)/2) * W/nf * 0.29'" 
pd="'2*int((nf+1)/2) * (W/nf + 0.29)'"
as="'int((nf+2)/2) * W/nf * 0.29'" 
ps="'2*int((nf+2)/2) * (W/nf + 0.29)'"
nrd="'0.29 / W'" nrs="'0.29 / W'"
sa=0 sb=0 sd=0
model=nfet_01v8_lvt
spiceprefix=X
}
C {lab_pin.sym} 450 -800 0 0 {name=l21 sig_type=std_logic lab=net13}
C {gnd.sym} 1560 -690 0 0 {name=l22 lab=GND}
C {lab_pin.sym} 1560 -1150 0 0 {name=l23 sig_type=std_logic lab=VDD
}
C {gnd.sym} 1460 -1020 0 0 {name=l28 lab=GND}
C {lab_pin.sym} 1440 -780 0 0 {name=l41 sig_type=std_logic lab=VBIASN1}
C {sky130_fd_pr/nfet_01v8_lvt.sym} 430 -870 0 0 {name=M14
L=0.15
W=1
nf=1
mult=1
ad="'int((nf+1)/2) * W/nf * 0.29'" 
pd="'2*int((nf+1)/2) * (W/nf + 0.29)'"
as="'int((nf+2)/2) * W/nf * 0.29'" 
ps="'2*int((nf+2)/2) * (W/nf + 0.29)'"
nrd="'0.29 / W'" nrs="'0.29 / W'"
sa=0 sb=0 sd=0
model=nfet_01v8_lvt
spiceprefix=X
}
C {gnd.sym} 650 -830 0 0 {name=l56 lab=GND}
C {gnd.sym} 1030 -840 0 0 {name=l57 lab=GND}
C {gnd.sym} 1380 -840 0 0 {name=l59 lab=GND}
C {gnd.sym} 1740 -840 0 0 {name=l61 lab=GND}
C {lab_pin.sym} 450 -950 0 0 {name=l42 sig_type=std_logic lab=n5}
C {lab_pin.sym} 600 -950 0 0 {name=l43 sig_type=std_logic lab=n6}
C {sky130_fd_pr/nfet_01v8_lvt.sym} 580 -870 0 0 {name=M18
L=0.15
W=1
nf=1
mult=1
ad="'int((nf+1)/2) * W/nf * 0.29'" 
pd="'2*int((nf+1)/2) * (W/nf + 0.29)'"
as="'int((nf+2)/2) * W/nf * 0.29'" 
ps="'2*int((nf+2)/2) * (W/nf + 0.29)'"
nrd="'0.29 / W'" nrs="'0.29 / W'"
sa=0 sb=0 sd=0
model=nfet_01v8_lvt
spiceprefix=X
}
C {sky130_fd_pr/nfet_01v8_lvt.sym} 780 -880 0 0 {name=M19
L=0.15
W=1
nf=1
mult=1
ad="'int((nf+1)/2) * W/nf * 0.29'" 
pd="'2*int((nf+1)/2) * (W/nf + 0.29)'"
as="'int((nf+2)/2) * W/nf * 0.29'" 
ps="'2*int((nf+2)/2) * (W/nf + 0.29)'"
nrd="'0.29 / W'" nrs="'0.29 / W'"
sa=0 sb=0 sd=0
model=nfet_01v8_lvt
spiceprefix=X
}
C {sky130_fd_pr/nfet_01v8_lvt.sym} 930 -880 0 0 {name=M20
L=0.15
W=1
nf=1
mult=1
ad="'int((nf+1)/2) * W/nf * 0.29'" 
pd="'2*int((nf+1)/2) * (W/nf + 0.29)'"
as="'int((nf+2)/2) * W/nf * 0.29'" 
ps="'2*int((nf+2)/2) * (W/nf + 0.29)'"
nrd="'0.29 / W'" nrs="'0.29 / W'"
sa=0 sb=0 sd=0
model=nfet_01v8_lvt
spiceprefix=X
}
C {sky130_fd_pr/nfet_01v8_lvt.sym} 1110 -880 0 0 {name=M21
L=0.15
W=1
nf=1
mult=1
ad="'int((nf+1)/2) * W/nf * 0.29'" 
pd="'2*int((nf+1)/2) * (W/nf + 0.29)'"
as="'int((nf+2)/2) * W/nf * 0.29'" 
ps="'2*int((nf+2)/2) * (W/nf + 0.29)'"
nrd="'0.29 / W'" nrs="'0.29 / W'"
sa=0 sb=0 sd=0
model=nfet_01v8_lvt
spiceprefix=X
}
C {sky130_fd_pr/nfet_01v8_lvt.sym} 1260 -880 0 0 {name=M22
L=0.15
W=1
nf=1
mult=1
ad="'int((nf+1)/2) * W/nf * 0.29'" 
pd="'2*int((nf+1)/2) * (W/nf + 0.29)'"
as="'int((nf+2)/2) * W/nf * 0.29'" 
ps="'2*int((nf+2)/2) * (W/nf + 0.29)'"
nrd="'0.29 / W'" nrs="'0.29 / W'"
sa=0 sb=0 sd=0
model=nfet_01v8_lvt
spiceprefix=X
}
C {sky130_fd_pr/nfet_01v8_lvt.sym} 1470 -880 0 0 {name=M23
L=0.15
W=1
nf=1
mult=1
ad="'int((nf+1)/2) * W/nf * 0.29'" 
pd="'2*int((nf+1)/2) * (W/nf + 0.29)'"
as="'int((nf+2)/2) * W/nf * 0.29'" 
ps="'2*int((nf+2)/2) * (W/nf + 0.29)'"
nrd="'0.29 / W'" nrs="'0.29 / W'"
sa=0 sb=0 sd=0
model=nfet_01v8_lvt
spiceprefix=X
}
C {sky130_fd_pr/nfet_01v8_lvt.sym} 1620 -880 0 0 {name=M24
L=0.15
W=1
nf=1
mult=1
ad="'int((nf+1)/2) * W/nf * 0.29'" 
pd="'2*int((nf+1)/2) * (W/nf + 0.29)'"
as="'int((nf+2)/2) * W/nf * 0.29'" 
ps="'2*int((nf+2)/2) * (W/nf + 0.29)'"
nrd="'0.29 / W'" nrs="'0.29 / W'"
sa=0 sb=0 sd=0
model=nfet_01v8_lvt
spiceprefix=X
}
C {sky130_fd_pr/res_high_po_5p73.sym} 630 -1010 0 0 {name=R2
W=5.73
L=30.4
model=res_high_po_5p73
spiceprefix=X
mult=1}
C {sky130_fd_pr/nfet_01v8_lvt.sym} 850 -220 0 0 {name=M2
L=0.15
W=40
nf=40
mult=1
ad="'int((nf+1)/2) * W/nf * 0.29'" 
pd="'2*int((nf+1)/2) * (W/nf + 0.29)'"
as="'int((nf+2)/2) * W/nf * 0.29'" 
ps="'2*int((nf+2)/2) * (W/nf + 0.29)'"
nrd="'0.29 / W'" nrs="'0.29 / W'"
sa=0 sb=0 sd=0
model=nfet_01v8_lvt
spiceprefix=X
}
C {sky130_fd_pr/nfet_01v8_lvt.sym} 1180 -220 0 0 {name=M3
L=0.15
W=40
nf=40
mult=1
ad="'int((nf+1)/2) * W/nf * 0.29'" 
pd="'2*int((nf+1)/2) * (W/nf + 0.29)'"
as="'int((nf+2)/2) * W/nf * 0.29'" 
ps="'2*int((nf+2)/2) * (W/nf + 0.29)'"
nrd="'0.29 / W'" nrs="'0.29 / W'"
sa=0 sb=0 sd=0
model=nfet_01v8_lvt
spiceprefix=X
}
C {sky130_fd_pr/nfet_01v8_lvt.sym} 1540 -220 0 0 {name=M4
L=0.15
W=40
nf=40
mult=1
ad="'int((nf+1)/2) * W/nf * 0.29'" 
pd="'2*int((nf+1)/2) * (W/nf + 0.29)'"
as="'int((nf+2)/2) * W/nf * 0.29'" 
ps="'2*int((nf+2)/2) * (W/nf + 0.29)'"
nrd="'0.29 / W'" nrs="'0.29 / W'"
sa=0 sb=0 sd=0
model=nfet_01v8_lvt
spiceprefix=X
}
C {gnd.sym} 1680 120 0 0 {name=l73 lab=GND}
C {cap_bank.sym} 1610 100 0 0 {name=X1}
C {lab_pin.sym} 1610 20 0 0 {name=l64 sig_type=std_logic lab=CTRL1}
C {lab_pin.sym} 1610 40 0 0 {name=l65 sig_type=std_logic lab=CTRL2}
C {lab_pin.sym} 1610 60 0 0 {name=l66 sig_type=std_logic lab=CTRL3}
C {lab_pin.sym} 1610 80 0 0 {name=l67 sig_type=std_logic lab=CTRL4}
C {lab_pin.sym} 1610 100 0 0 {name=l68 sig_type=std_logic lab=CTRL5}
C {gnd.sym} 1530 120 0 0 {name=l69 lab=GND}
C {cap_bank.sym} 1460 100 0 0 {name=X2}
C {lab_pin.sym} 1460 20 0 0 {name=l70 sig_type=std_logic lab=CTRL1}
C {lab_pin.sym} 1460 40 0 0 {name=l71 sig_type=std_logic lab=CTRL2}
C {lab_pin.sym} 1460 60 0 0 {name=l72 sig_type=std_logic lab=CTRL3}
C {lab_pin.sym} 1460 80 0 0 {name=l74 sig_type=std_logic lab=CTRL4}
C {lab_pin.sym} 1460 100 0 0 {name=l75 sig_type=std_logic lab=CTRL5}
C {gnd.sym} 1340 120 0 0 {name=l76 lab=GND}
C {cap_bank.sym} 1270 100 0 0 {name=X3}
C {lab_pin.sym} 1270 20 0 0 {name=l77 sig_type=std_logic lab=CTRL1}
C {lab_pin.sym} 1270 40 0 0 {name=l78 sig_type=std_logic lab=CTRL2}
C {lab_pin.sym} 1270 60 0 0 {name=l79 sig_type=std_logic lab=CTRL3}
C {lab_pin.sym} 1270 80 0 0 {name=l80 sig_type=std_logic lab=CTRL4}
C {lab_pin.sym} 1270 100 0 0 {name=l81 sig_type=std_logic lab=CTRL5}
C {gnd.sym} 1190 120 0 0 {name=l82 lab=GND}
C {cap_bank.sym} 1120 100 0 0 {name=X4}
C {lab_pin.sym} 1120 20 0 0 {name=l83 sig_type=std_logic lab=CTRL1}
C {lab_pin.sym} 1120 40 0 0 {name=l84 sig_type=std_logic lab=CTRL2}
C {lab_pin.sym} 1120 60 0 0 {name=l85 sig_type=std_logic lab=CTRL3}
C {lab_pin.sym} 1120 80 0 0 {name=l86 sig_type=std_logic lab=CTRL4}
C {lab_pin.sym} 1120 100 0 0 {name=l87 sig_type=std_logic lab=CTRL5}
C {gnd.sym} 990 120 0 0 {name=l88 lab=GND}
C {cap_bank.sym} 920 100 0 0 {name=X5}
C {lab_pin.sym} 920 20 0 0 {name=l89 sig_type=std_logic lab=CTRL1}
C {lab_pin.sym} 920 40 0 0 {name=l90 sig_type=std_logic lab=CTRL2}
C {lab_pin.sym} 920 60 0 0 {name=l91 sig_type=std_logic lab=CTRL3}
C {lab_pin.sym} 920 80 0 0 {name=l92 sig_type=std_logic lab=CTRL4}
C {lab_pin.sym} 920 100 0 0 {name=l93 sig_type=std_logic lab=CTRL5}
C {gnd.sym} 840 120 0 0 {name=l94 lab=GND}
C {cap_bank.sym} 770 100 0 0 {name=X6}
C {lab_pin.sym} 770 20 0 0 {name=l95 sig_type=std_logic lab=CTRL1}
C {lab_pin.sym} 770 40 0 0 {name=l96 sig_type=std_logic lab=CTRL2}
C {lab_pin.sym} 770 60 0 0 {name=l97 sig_type=std_logic lab=CTRL3}
C {lab_pin.sym} 770 80 0 0 {name=l98 sig_type=std_logic lab=CTRL4}
C {lab_pin.sym} 770 100 0 0 {name=l99 sig_type=std_logic lab=CTRL5}
C {gnd.sym} 640 130 0 0 {name=l100 lab=GND}
C {cap_bank.sym} 570 110 0 0 {name=X7}
C {lab_pin.sym} 570 30 0 0 {name=l101 sig_type=std_logic lab=CTRL1}
C {lab_pin.sym} 570 50 0 0 {name=l102 sig_type=std_logic lab=CTRL2}
C {lab_pin.sym} 570 70 0 0 {name=l103 sig_type=std_logic lab=CTRL3}
C {lab_pin.sym} 570 90 0 0 {name=l104 sig_type=std_logic lab=CTRL4}
C {lab_pin.sym} 570 110 0 0 {name=l105 sig_type=std_logic lab=CTRL5}
C {gnd.sym} 490 130 0 0 {name=l106 lab=GND}
C {cap_bank.sym} 420 110 0 0 {name=X8}
C {lab_pin.sym} 420 30 0 0 {name=l107 sig_type=std_logic lab=CTRL1}
C {lab_pin.sym} 420 50 0 0 {name=l108 sig_type=std_logic lab=CTRL2}
C {lab_pin.sym} 420 70 0 0 {name=l109 sig_type=std_logic lab=CTRL3}
C {lab_pin.sym} 420 90 0 0 {name=l110 sig_type=std_logic lab=CTRL4}
C {lab_pin.sym} 420 110 0 0 {name=l111 sig_type=std_logic lab=CTRL5}
C {sky130_fd_pr/res_high_po_5p73.sym} 100 -590 0 0 {name=R9
W=5.73
L=17
model=res_high_po_5p73
spiceprefix=X
mult=1}
C {gnd.sym} 100 -550 0 0 {name=l62 lab=GND}
C {lab_pin.sym} 100 -650 0 0 {name=l63 sig_type=std_logic lab=VDD
}
C {sky130_fd_pr/res_high_po_2p85.sym} 480 -450 0 0 {name=R10
W=2.85
L=7.6
model=res_high_po_2p85
spiceprefix=X
mult=1}
C {sky130_fd_pr/res_high_po_2p85.sym} 630 -450 0 0 {name=R11
W=2.85
L=7.6
model=res_high_po_2p85
spiceprefix=X
mult=1}
C {sky130_fd_pr/res_high_po_2p85.sym} 840 -460 0 0 {name=R12
W=2.85
L=7.6
model=res_high_po_2p85
spiceprefix=X
mult=1}
C {sky130_fd_pr/res_high_po_2p85.sym} 980 -460 0 0 {name=R13
W=2.85
L=7.6
model=res_high_po_2p85
spiceprefix=X
mult=1}
C {sky130_fd_pr/res_high_po_2p85.sym} 1160 -460 0 0 {name=R14
W=2.85
L=7.6
model=res_high_po_2p85
spiceprefix=X
mult=1}
C {sky130_fd_pr/res_high_po_2p85.sym} 1310 -460 0 0 {name=R15
W=2.85
L=7.6
model=res_high_po_2p85
spiceprefix=X
mult=1}
C {sky130_fd_pr/res_high_po_2p85.sym} 1520 -460 0 0 {name=R16
W=2.85
L=7.6
model=res_high_po_2p85
spiceprefix=X
mult=1}
C {sky130_fd_pr/res_high_po_2p85.sym} 1670 -460 0 0 {name=R17
W=2.85
L=7.6
model=res_high_po_2p85
spiceprefix=X
mult=1}
C {gnd.sym} 2030 -810 0 0 {name=l129 lab=GND}
C {sky130_fd_pr/nfet_01v8_lvt.sym} 2010 -970 0 0 {name=M41
L=0.15
W=12
nf=12
mult=1
ad="'int((nf+1)/2) * W/nf * 0.29'" 
pd="'2*int((nf+1)/2) * (W/nf + 0.29)'"
as="'int((nf+2)/2) * W/nf * 0.29'" 
ps="'2*int((nf+2)/2) * (W/nf + 0.29)'"
nrd="'0.29 / W'" nrs="'0.29 / W'"
sa=0 sb=0 sd=0
model=nfet_01v8_lvt
spiceprefix=X
}
C {lab_pin.sym} 2030 -1050 0 0 {name=l136 sig_type=std_logic lab=VDD
}
C {gnd.sym} 2060 -970 0 0 {name=l137 lab=GND}
C {gnd.sym} 1910 -830 0 0 {name=l138 lab=GND}
C {sky130_fd_pr/cap_mim_m3_1.sym} 1910 -900 0 0 {name=C2 model=cap_mim_m3_1 W=20 L=30 MF=1 spiceprefix=X}
C {lab_pin.sym} 500 -1730 0 0 {name=l113 sig_type=std_logic lab=VDD
}
C {gnd.sym} 630 -1420 0 0 {name=l115 lab=GND}
C {gnd.sym} 430 -1290 0 0 {name=l117 lab=GND}
C {sky130_fd_pr/nfet_01v8_lvt.sym} 410 -1460 0 0 {name=M25
L=0.15
W=4
nf=4
mult=1
ad="'int((nf+1)/2) * W/nf * 0.29'" 
pd="'2*int((nf+1)/2) * (W/nf + 0.29)'"
as="'int((nf+2)/2) * W/nf * 0.29'" 
ps="'2*int((nf+2)/2) * (W/nf + 0.29)'"
nrd="'0.29 / W'" nrs="'0.29 / W'"
sa=0 sb=0 sd=0
model=nfet_01v8_lvt
spiceprefix=X
}
C {sky130_fd_pr/cap_mim_m3_1.sym} 430 -1360 0 0 {name=C1 model=cap_mim_m3_1 W=20 L=30 MF=1 spiceprefix=X}
C {sky130_fd_pr/nfet_01v8_lvt.sym} 560 -1460 0 0 {name=M26
L=0.15
W=4
nf=4
mult=1
ad="'int((nf+1)/2) * W/nf * 0.29'" 
pd="'2*int((nf+1)/2) * (W/nf + 0.29)'"
as="'int((nf+2)/2) * W/nf * 0.29'" 
ps="'2*int((nf+2)/2) * (W/nf + 0.29)'"
nrd="'0.29 / W'" nrs="'0.29 / W'"
sa=0 sb=0 sd=0
model=nfet_01v8_lvt
spiceprefix=X
}
C {lab_pin.sym} 900 -1730 0 0 {name=l119 sig_type=std_logic lab=VDD
}
C {gnd.sym} 1030 -1420 0 0 {name=l121 lab=GND}
C {sky130_fd_pr/nfet_01v8_lvt.sym} 810 -1460 0 0 {name=M27
L=0.15
W=4
nf=4
mult=1
ad="'int((nf+1)/2) * W/nf * 0.29'" 
pd="'2*int((nf+1)/2) * (W/nf + 0.29)'"
as="'int((nf+2)/2) * W/nf * 0.29'" 
ps="'2*int((nf+2)/2) * (W/nf + 0.29)'"
nrd="'0.29 / W'" nrs="'0.29 / W'"
sa=0 sb=0 sd=0
model=nfet_01v8_lvt
spiceprefix=X
}
C {sky130_fd_pr/nfet_01v8_lvt.sym} 960 -1460 0 0 {name=M28
L=0.15
W=4
nf=4
mult=1
ad="'int((nf+1)/2) * W/nf * 0.29'" 
pd="'2*int((nf+1)/2) * (W/nf + 0.29)'"
as="'int((nf+2)/2) * W/nf * 0.29'" 
ps="'2*int((nf+2)/2) * (W/nf + 0.29)'"
nrd="'0.29 / W'" nrs="'0.29 / W'"
sa=0 sb=0 sd=0
model=nfet_01v8_lvt
spiceprefix=X
}
C {lab_pin.sym} 360 -1460 0 0 {name=l123 sig_type=std_logic lab=n5}
C {lab_pin.sym} 510 -1460 0 0 {name=l124 sig_type=std_logic lab=n6}
C {lab_pin.sym} 1130 -970 0 0 {name=l125 sig_type=std_logic lab=n7}
C {lab_pin.sym} 1280 -970 0 0 {name=l126 sig_type=std_logic lab=n8}
C {lab_pin.sym} 760 -1460 0 0 {name=l127 sig_type=std_logic lab=n7}
C {lab_pin.sym} 910 -1460 0 0 {name=l128 sig_type=std_logic lab=n8}
C {lab_pin.sym} 1350 -2000 0 0 {name=l122 sig_type=std_logic lab=VDD
}
C {sky130_fd_pr/pfet_01v8_lvt.sym} 1330 -1940 0 0 {name=M29
L=0.35
W=30
nf=30
mult=1
ad="'int((nf+1)/2) * W/nf * 0.29'" 
pd="'2*int((nf+1)/2) * (W/nf + 0.29)'"
as="'int((nf+2)/2) * W/nf * 0.29'" 
ps="'2*int((nf+2)/2) * (W/nf + 0.29)'"
nrd="'0.29 / W'" nrs="'0.29 / W'"
sa=0 sb=0 sd=0
model=pfet_01v8_lvt
spiceprefix=X
}
C {sky130_fd_pr/pfet_01v8_lvt.sym} 1420 -1850 0 0 {name=M30
L=0.35
W=10
nf=10
mult=1
ad="'int((nf+1)/2) * W/nf * 0.29'" 
pd="'2*int((nf+1)/2) * (W/nf + 0.29)'"
as="'int((nf+2)/2) * W/nf * 0.29'" 
ps="'2*int((nf+2)/2) * (W/nf + 0.29)'"
nrd="'0.29 / W'" nrs="'0.29 / W'"
sa=0 sb=0 sd=0
model=pfet_01v8_lvt
spiceprefix=X
}
C {sky130_fd_pr/pfet_01v8_lvt.sym} 1260 -1850 0 0 {name=M31
L=0.35
W=10
nf=10
mult=1
ad="'int((nf+1)/2) * W/nf * 0.29'" 
pd="'2*int((nf+1)/2) * (W/nf + 0.29)'"
as="'int((nf+2)/2) * W/nf * 0.29'" 
ps="'2*int((nf+2)/2) * (W/nf + 0.29)'"
nrd="'0.29 / W'" nrs="'0.29 / W'"
sa=0 sb=0 sd=0
model=pfet_01v8_lvt
spiceprefix=X
}
C {vsource.sym} 1190 -1950 0 0 {name=V14 value="DC 2" 
}
C {gnd.sym} 1190 -1920 0 0 {name=l130 lab=GND}
C {gnd.sym} 1360 -1630 0 0 {name=l131 lab=GND}
C {lab_pin.sym} 1180 -1850 0 0 {name=l132 sig_type=std_logic lab=Amp}
C {lab_pin.sym} 1490 -1950 0 0 {name=l133 sig_type=std_logic lab=VDD
}
C {lab_pin.sym} 1280 -1800 0 0 {name=l135 sig_type=std_logic lab=test0}
C {lab_pin.sym} 1440 -1800 0 0 {name=l134 sig_type=std_logic lab=test2}
C {lab_pin.sym} 1790 -1880 0 0 {name=l140 sig_type=std_logic lab=VDD
}
C {sky130_fd_pr/pfet_01v8_lvt.sym} 1770 -1820 0 0 {name=M36
L=0.35
W=45
nf=45
mult=1
ad="'int((nf+1)/2) * W/nf * 0.29'" 
pd="'2*int((nf+1)/2) * (W/nf + 0.29)'"
as="'int((nf+2)/2) * W/nf * 0.29'" 
ps="'2*int((nf+2)/2) * (W/nf + 0.29)'"
nrd="'0.29 / W'" nrs="'0.29 / W'"
sa=0 sb=0 sd=0
model=pfet_01v8_lvt
spiceprefix=X
}
C {sky130_fd_pr/pfet_01v8_lvt.sym} 1860 -1730 0 0 {name=M37
L=0.35
W=30
nf=30
mult=1
ad="'int((nf+1)/2) * W/nf * 0.29'" 
pd="'2*int((nf+1)/2) * (W/nf + 0.29)'"
as="'int((nf+2)/2) * W/nf * 0.29'" 
ps="'2*int((nf+2)/2) * (W/nf + 0.29)'"
nrd="'0.29 / W'" nrs="'0.29 / W'"
sa=0 sb=0 sd=0
model=pfet_01v8_lvt
spiceprefix=X
}
C {sky130_fd_pr/pfet_01v8_lvt.sym} 1700 -1730 0 0 {name=M38
L=0.35
W=30
nf=30
mult=1
ad="'int((nf+1)/2) * W/nf * 0.29'" 
pd="'2*int((nf+1)/2) * (W/nf + 0.29)'"
as="'int((nf+2)/2) * W/nf * 0.29'" 
ps="'2*int((nf+2)/2) * (W/nf + 0.29)'"
nrd="'0.29 / W'" nrs="'0.29 / W'"
sa=0 sb=0 sd=0
model=pfet_01v8_lvt
spiceprefix=X
}
C {vsource.sym} 1630 -1830 0 0 {name=V12 value="DC 2" 
}
C {gnd.sym} 1630 -1800 0 0 {name=l141 lab=GND}
C {gnd.sym} 1800 -1510 0 0 {name=l142 lab=GND}
C {lab_pin.sym} 1930 -1830 0 0 {name=l143 sig_type=std_logic lab=VDD
}
C {sky130_fd_pr/nfet_01v8_lvt.sym} 1860 -1630 0 0 {name=M39
L=0.15
W=10
nf=10
mult=1
ad="'int((nf+1)/2) * W/nf * 0.29'" 
pd="'2*int((nf+1)/2) * (W/nf + 0.29)'"
as="'int((nf+2)/2) * W/nf * 0.29'" 
ps="'2*int((nf+2)/2) * (W/nf + 0.29)'"
nrd="'0.29 / W'" nrs="'0.29 / W'"
sa=0 sb=0 sd=0
model=nfet_01v8_lvt
spiceprefix=X
}
C {sky130_fd_pr/nfet_01v8_lvt.sym} 1700 -1630 0 0 {name=M40
L=0.15
W=10
nf=10
mult=1
ad="'int((nf+1)/2) * W/nf * 0.29'" 
pd="'2*int((nf+1)/2) * (W/nf + 0.29)'"
as="'int((nf+2)/2) * W/nf * 0.29'" 
ps="'2*int((nf+2)/2) * (W/nf + 0.29)'"
nrd="'0.29 / W'" nrs="'0.29 / W'"
sa=0 sb=0 sd=0
model=nfet_01v8_lvt
spiceprefix=X
}
C {vsource.sym} 2010 -1690 0 0 {name=V15 value="DC 1" 
}
C {gnd.sym} 2010 -1660 0 0 {name=l144 lab=GND}
C {lab_pin.sym} 1700 -1860 0 0 {name=l145 sig_type=std_logic lab=test3}
C {lab_pin.sym} 930 -1390 0 0 {name=l139 sig_type=std_logic lab=Amp}
C {lab_pin.sym} 1360 -1820 0 0 {name=l146 sig_type=std_logic lab=Vop}
C {lab_pin.sym} 2030 -920 0 0 {name=l147 sig_type=std_logic lab=Vop}
C {sky130_fd_pr/res_high_po_5p73.sym} 490 -1010 0 0 {name=R1
W=5.73
L=30.4
model=res_high_po_5p73
spiceprefix=X
mult=1}
C {sky130_fd_pr/res_high_po_5p73.sym} 840 -1020 0 0 {name=R3
W=5.73
L=30.4
model=res_high_po_5p73
spiceprefix=X
mult=1}
C {sky130_fd_pr/res_high_po_5p73.sym} 990 -1020 0 0 {name=R4
W=5.73
L=30.4
model=res_high_po_5p73
spiceprefix=X
mult=1}
C {sky130_fd_pr/res_high_po_5p73.sym} 1170 -1020 0 0 {name=R5
W=5.73
L=30.4
model=res_high_po_5p73
spiceprefix=X
mult=1}
C {sky130_fd_pr/res_high_po_5p73.sym} 1320 -1020 0 0 {name=R6
W=5.73
L=30.4
model=res_high_po_5p73
spiceprefix=X
mult=1}
C {sky130_fd_pr/res_high_po_5p73.sym} 1530 -1020 0 0 {name=R7
W=5.73
L=30.4
model=res_high_po_5p73
spiceprefix=X
mult=1}
C {sky130_fd_pr/res_high_po_5p73.sym} 1670 -1020 0 0 {name=R8
W=5.73
L=30.4
model=res_high_po_5p73
spiceprefix=X
mult=1}
C {sky130_fd_pr/res_high_po_2p85.sym} 1280 -1750 0 0 {name=R19
W=2.85
L=7.6
model=res_high_po_2p85
spiceprefix=X
mult=1}
C {sky130_fd_pr/res_high_po_2p85.sym} 1440 -1750 0 0 {name=R20
W=2.85
L=11.4
model=res_high_po_2p85
spiceprefix=X
mult=1}
C {sky130_fd_pr/res_high_po_2p85.sym} 570 -1360 0 0 {name=R18
W=2.85
L=42
model=res_high_po_2p85
spiceprefix=X
mult=1}
C {sky130_fd_pr/res_high_po_2p85.sym} 2120 -890 0 0 {name=R21
W=2.85
L=42
model=res_high_po_2p85
spiceprefix=X
mult=1}
C {sky130_fd_pr/nfet_01v8_lvt.sym} 850 -780 0 0 {name=M15
L=0.15
W=20
nf=20
mult=1
ad="'int((nf+1)/2) * W/nf * 0.29'" 
pd="'2*int((nf+1)/2) * (W/nf + 0.29)'"
as="'int((nf+2)/2) * W/nf * 0.29'" 
ps="'2*int((nf+2)/2) * (W/nf + 0.29)'"
nrd="'0.29 / W'" nrs="'0.29 / W'"
sa=0 sb=0 sd=0
model=nfet_01v8_lvt
spiceprefix=X
}
C {sky130_fd_pr/nfet_01v8_lvt.sym} 1180 -780 0 0 {name=M16
L=0.15
W=20
nf=20
mult=1
ad="'int((nf+1)/2) * W/nf * 0.29'" 
pd="'2*int((nf+1)/2) * (W/nf + 0.29)'"
as="'int((nf+2)/2) * W/nf * 0.29'" 
ps="'2*int((nf+2)/2) * (W/nf + 0.29)'"
nrd="'0.29 / W'" nrs="'0.29 / W'"
sa=0 sb=0 sd=0
model=nfet_01v8_lvt
spiceprefix=X
}
C {sky130_fd_pr/nfet_01v8_lvt.sym} 1540 -780 0 0 {name=M17
L=0.15
W=20
nf=20
mult=1
ad="'int((nf+1)/2) * W/nf * 0.29'" 
pd="'2*int((nf+1)/2) * (W/nf + 0.29)'"
as="'int((nf+2)/2) * W/nf * 0.29'" 
ps="'2*int((nf+2)/2) * (W/nf + 0.29)'"
nrd="'0.29 / W'" nrs="'0.29 / W'"
sa=0 sb=0 sd=0
model=nfet_01v8_lvt
spiceprefix=X
}
C {vsource.sym} -390 -340 0 0 {name=V17 value="dc 2.8"}
C {gnd.sym} -390 -310 0 0 {name=l148 lab=GND}
C {gnd.sym} -390 -220 0 0 {name=l150 lab=GND}
C {gnd.sym} -390 -130 0 0 {name=l152 lab=GND}
C {gnd.sym} -390 -40 0 0 {name=l154 lab=GND}
C {gnd.sym} -390 50 0 0 {name=l156 lab=GND}
C {vsource.sym} -390 -250 0 0 {name=V18 value="dc 2.8"}
C {vsource.sym} -390 -160 0 0 {name=V19 value="dc 2.8"}
C {vsource.sym} -390 -70 0 0 {name=V20 value="dc 2.8"}
C {vsource.sym} -390 20 0 0 {name=V21 value="dc 2.8"}
